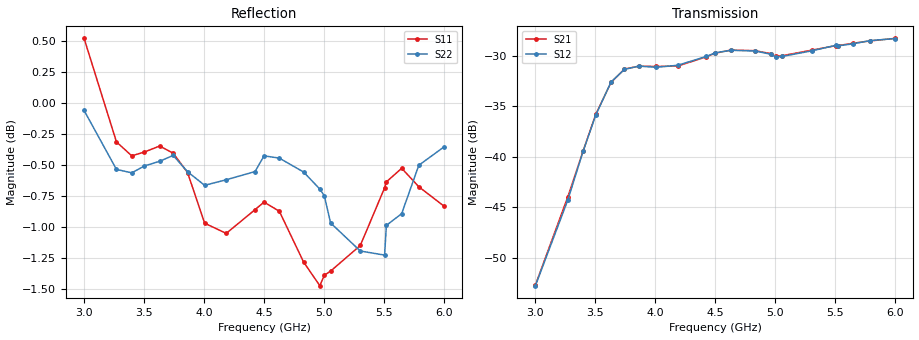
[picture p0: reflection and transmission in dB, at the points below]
!  26/11/2025  17:12:54
! Ref Plane: 0.000 mm
# MHZ S MA R  50
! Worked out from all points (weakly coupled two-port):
!   401 points, 3 GHz to 6 GHz, reference 50 ohm
!   highest |S21| = -28.30 dB at 6 GHz (marker M1); lowest = -52.7 dB at 3 GHz (marker M2)
!   lowest |S11| = -1.5 dB at 4.965 GHz (marker M3), VSWR 11.84, Z = 9.18 - j53.8 ohm
!   |S11| at or under -10 dB: nowhere
!   |S22| runs from -1.2 to 0.0 dB; largest |S21 - S12| = 0.0016
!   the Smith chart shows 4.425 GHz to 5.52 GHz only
!   S11 on the Smith chart (normalised r, x): 4.425 GHz: 0.10, +1.03; 4.628 GHz: 1.27, +4.78; 4.83 GHz: 0.53, -2.45; 5.055 GHz: 0.11, -0.68; 5.303 GHz: 0.07, -0.01; 5.52 GHz: 0.05, +0.60
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3000  1.062 -137.0  0.002323 46.2  0.002305 49.0  0.9933 -105.7
3270  0.9647 152.6  0.006331 -19.5  0.00611 -15.9  0.9404 -170.3
3397.5  0.9523 109.1  0.01067 -59.7  0.01064 -58.8  0.9374 151.0
3502.5  0.9557 66.2  0.01617 -100.3  0.01603 -99.1  0.9434 113.2
3630  0.961 11.1  0.02328 -156.5  0.02338 -155.2  0.9475 58.4
3742.5  0.9547 -38.6  0.02711 153.5  0.02702 155.0  0.9527 10.4
3862.5  0.9377 -86.3  0.02802 104.1  0.02803 105.8  0.9384 -38.0
4005  0.8946 -137.9  0.02792 53.1  0.02767 54.3  0.9266 -87.7
4185  0.8862 164.8  0.02804 -3.7  0.02829 -1.6  0.9314 -144.3
4425  0.9059 88.1  0.03116 -76.3  0.03129 -74.8  0.9385 142.2
4500  0.9123 63.7  0.03249 -100.5  0.03262 -99.0  0.9523 119.3
4627.5  0.9046 22.2  0.03363 -141.0  0.03356 -139.8  0.9503 80.0
4830  0.8629 -42.9  0.03342 155.1  0.03331 156.8  0.9381 18.9
4965  0.8442 -85.0  0.03229 116.1  0.03205 117.6  0.9234 -19.8
5002.5  0.8524 -96.3  0.0313 106.0  0.03101 107.4  0.9177 -31.7
5055  0.8557 -111.0  0.03154 91.7  0.03129 92.5  0.8948 -47.4
5302.5  0.8763 -178.4  0.0336 25.2  0.03334 26.6  0.8718 -118.3
5505  0.9244 120.6  0.0354 -31.8  0.03553 -29.7  0.8685 -173.2
5520  0.9296 117.9  0.03537 -35.3  0.03529 -33.3  0.8928 -178.0
5647.5  0.9414 80.6  0.03637 -72.5  0.03612 -70.1  0.9026 146.3
5790  0.9254 40.3  0.03734 -113.1  0.03748 -111.3  0.944 107.3
6000  0.9089 -21.0  0.03844 -173.3  0.03837 -171.9  0.9602 53.4
